VERSION 5.7 ;
BUSBITCHARS "[]" ;
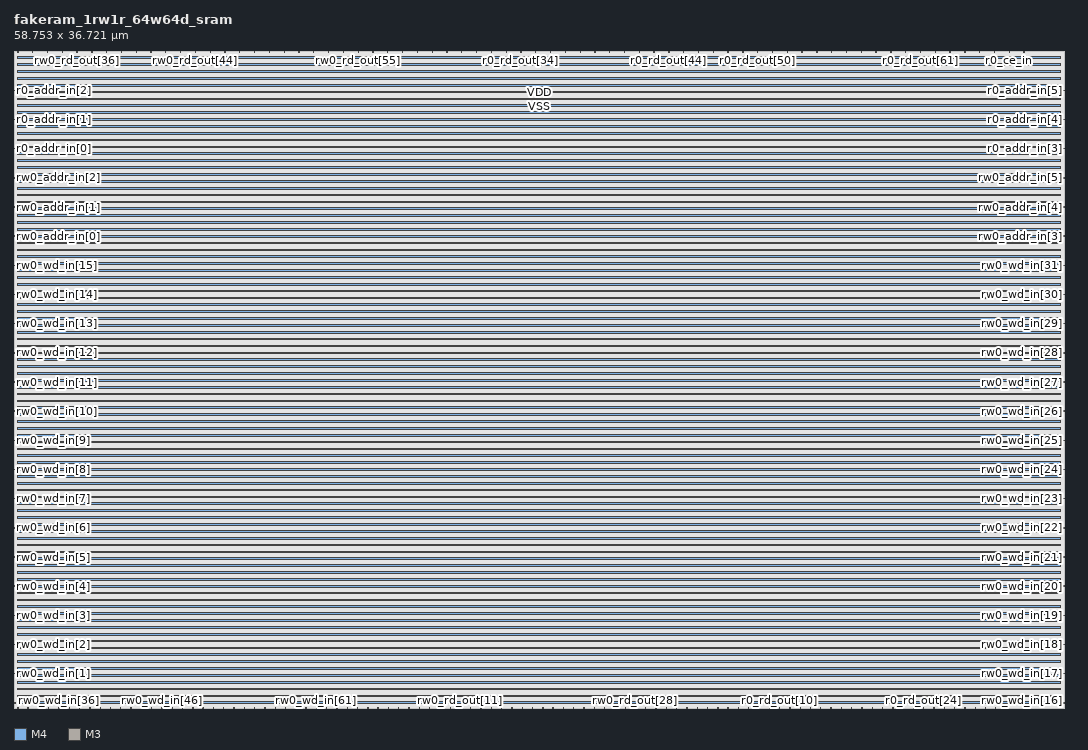
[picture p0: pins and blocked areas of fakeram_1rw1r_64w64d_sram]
MACRO fakeram_1rw1r_64w64d_sram
  FOREIGN fakeram_1rw1r_64w64d_sram 0 0 ;
  SYMMETRY X Y R90 ;
  SIZE 58.753 BY 36.721 ;
  CLASS BLOCK ;
  PIN rw0_wd_in[0]
    DIRECTION INPUT ;
    USE SIGNAL ;
    SHAPE ABUTMENT ;
    PORT
      LAYER M4 ;
      RECT 0.000 0.276 0.072 0.300 ;
    END
  END rw0_wd_in[0]
  PIN rw0_wd_in[1]
    DIRECTION INPUT ;
    USE SIGNAL ;
    SHAPE ABUTMENT ;
    PORT
      LAYER M4 ;
      RECT 0.000 1.908 0.072 1.932 ;
    END
  END rw0_wd_in[1]
  PIN rw0_wd_in[2]
    DIRECTION INPUT ;
    USE SIGNAL ;
    SHAPE ABUTMENT ;
    PORT
      LAYER M4 ;
      RECT 0.000 3.540 0.072 3.564 ;
    END
  END rw0_wd_in[2]
  PIN rw0_wd_in[3]
    DIRECTION INPUT ;
    USE SIGNAL ;
    SHAPE ABUTMENT ;
    PORT
      LAYER M4 ;
      RECT 0.000 5.172 0.072 5.196 ;
    END
  END rw0_wd_in[3]
  PIN rw0_wd_in[4]
    DIRECTION INPUT ;
    USE SIGNAL ;
    SHAPE ABUTMENT ;
    PORT
      LAYER M4 ;
      RECT 0.000 6.804 0.072 6.828 ;
    END
  END rw0_wd_in[4]
  PIN rw0_wd_in[5]
    DIRECTION INPUT ;
    USE SIGNAL ;
    SHAPE ABUTMENT ;
    PORT
      LAYER M4 ;
      RECT 0.000 8.436 0.072 8.460 ;
    END
  END rw0_wd_in[5]
  PIN rw0_wd_in[6]
    DIRECTION INPUT ;
    USE SIGNAL ;
    SHAPE ABUTMENT ;
    PORT
      LAYER M4 ;
      RECT 0.000 10.068 0.072 10.092 ;
    END
  END rw0_wd_in[6]
  PIN rw0_wd_in[7]
    DIRECTION INPUT ;
    USE SIGNAL ;
    SHAPE ABUTMENT ;
    PORT
      LAYER M4 ;
      RECT 0.000 11.700 0.072 11.724 ;
    END
  END rw0_wd_in[7]
  PIN rw0_wd_in[8]
    DIRECTION INPUT ;
    USE SIGNAL ;
    SHAPE ABUTMENT ;
    PORT
      LAYER M4 ;
      RECT 0.000 13.332 0.072 13.356 ;
    END
  END rw0_wd_in[8]
  PIN rw0_wd_in[9]
    DIRECTION INPUT ;
    USE SIGNAL ;
    SHAPE ABUTMENT ;
    PORT
      LAYER M4 ;
      RECT 0.000 14.964 0.072 14.988 ;
    END
  END rw0_wd_in[9]
  PIN rw0_wd_in[10]
    DIRECTION INPUT ;
    USE SIGNAL ;
    SHAPE ABUTMENT ;
    PORT
      LAYER M4 ;
      RECT 0.000 16.596 0.072 16.620 ;
    END
  END rw0_wd_in[10]
  PIN rw0_wd_in[11]
    DIRECTION INPUT ;
    USE SIGNAL ;
    SHAPE ABUTMENT ;
    PORT
      LAYER M4 ;
      RECT 0.000 18.228 0.072 18.252 ;
    END
  END rw0_wd_in[11]
  PIN rw0_wd_in[12]
    DIRECTION INPUT ;
    USE SIGNAL ;
    SHAPE ABUTMENT ;
    PORT
      LAYER M4 ;
      RECT 0.000 19.860 0.072 19.884 ;
    END
  END rw0_wd_in[12]
  PIN rw0_wd_in[13]
    DIRECTION INPUT ;
    USE SIGNAL ;
    SHAPE ABUTMENT ;
    PORT
      LAYER M4 ;
      RECT 0.000 21.492 0.072 21.516 ;
    END
  END rw0_wd_in[13]
  PIN rw0_wd_in[14]
    DIRECTION INPUT ;
    USE SIGNAL ;
    SHAPE ABUTMENT ;
    PORT
      LAYER M4 ;
      RECT 0.000 23.124 0.072 23.148 ;
    END
  END rw0_wd_in[14]
  PIN rw0_wd_in[15]
    DIRECTION INPUT ;
    USE SIGNAL ;
    SHAPE ABUTMENT ;
    PORT
      LAYER M4 ;
      RECT 0.000 24.756 0.072 24.780 ;
    END
  END rw0_wd_in[15]
  PIN rw0_wd_in[16]
    DIRECTION INPUT ;
    USE SIGNAL ;
    SHAPE ABUTMENT ;
    PORT
      LAYER M4 ;
      RECT 58.681 0.276 58.753 0.300 ;
    END
  END rw0_wd_in[16]
  PIN rw0_wd_in[17]
    DIRECTION INPUT ;
    USE SIGNAL ;
    SHAPE ABUTMENT ;
    PORT
      LAYER M4 ;
      RECT 58.681 1.908 58.753 1.932 ;
    END
  END rw0_wd_in[17]
  PIN rw0_wd_in[18]
    DIRECTION INPUT ;
    USE SIGNAL ;
    SHAPE ABUTMENT ;
    PORT
      LAYER M4 ;
      RECT 58.681 3.540 58.753 3.564 ;
    END
  END rw0_wd_in[18]
  PIN rw0_wd_in[19]
    DIRECTION INPUT ;
    USE SIGNAL ;
    SHAPE ABUTMENT ;
    PORT
      LAYER M4 ;
      RECT 58.681 5.172 58.753 5.196 ;
    END
  END rw0_wd_in[19]
  PIN rw0_wd_in[20]
    DIRECTION INPUT ;
    USE SIGNAL ;
    SHAPE ABUTMENT ;
    PORT
      LAYER M4 ;
      RECT 58.681 6.804 58.753 6.828 ;
    END
  END rw0_wd_in[20]
  PIN rw0_wd_in[21]
    DIRECTION INPUT ;
    USE SIGNAL ;
    SHAPE ABUTMENT ;
    PORT
      LAYER M4 ;
      RECT 58.681 8.436 58.753 8.460 ;
    END
  END rw0_wd_in[21]
  PIN rw0_wd_in[22]
    DIRECTION INPUT ;
    USE SIGNAL ;
    SHAPE ABUTMENT ;
    PORT
      LAYER M4 ;
      RECT 58.681 10.068 58.753 10.092 ;
    END
  END rw0_wd_in[22]
  PIN rw0_wd_in[23]
    DIRECTION INPUT ;
    USE SIGNAL ;
    SHAPE ABUTMENT ;
    PORT
      LAYER M4 ;
      RECT 58.681 11.700 58.753 11.724 ;
    END
  END rw0_wd_in[23]
  PIN rw0_wd_in[24]
    DIRECTION INPUT ;
    USE SIGNAL ;
    SHAPE ABUTMENT ;
    PORT
      LAYER M4 ;
      RECT 58.681 13.332 58.753 13.356 ;
    END
  END rw0_wd_in[24]
  PIN rw0_wd_in[25]
    DIRECTION INPUT ;
    USE SIGNAL ;
    SHAPE ABUTMENT ;
    PORT
      LAYER M4 ;
      RECT 58.681 14.964 58.753 14.988 ;
    END
  END rw0_wd_in[25]
  PIN rw0_wd_in[26]
    DIRECTION INPUT ;
    USE SIGNAL ;
    SHAPE ABUTMENT ;
    PORT
      LAYER M4 ;
      RECT 58.681 16.596 58.753 16.620 ;
    END
  END rw0_wd_in[26]
  PIN rw0_wd_in[27]
    DIRECTION INPUT ;
    USE SIGNAL ;
    SHAPE ABUTMENT ;
    PORT
      LAYER M4 ;
      RECT 58.681 18.228 58.753 18.252 ;
    END
  END rw0_wd_in[27]
  PIN rw0_wd_in[28]
    DIRECTION INPUT ;
    USE SIGNAL ;
    SHAPE ABUTMENT ;
    PORT
      LAYER M4 ;
      RECT 58.681 19.860 58.753 19.884 ;
    END
  END rw0_wd_in[28]
  PIN rw0_wd_in[29]
    DIRECTION INPUT ;
    USE SIGNAL ;
    SHAPE ABUTMENT ;
    PORT
      LAYER M4 ;
      RECT 58.681 21.492 58.753 21.516 ;
    END
  END rw0_wd_in[29]
  PIN rw0_wd_in[30]
    DIRECTION INPUT ;
    USE SIGNAL ;
    SHAPE ABUTMENT ;
    PORT
      LAYER M4 ;
      RECT 58.681 23.124 58.753 23.148 ;
    END
  END rw0_wd_in[30]
  PIN rw0_wd_in[31]
    DIRECTION INPUT ;
    USE SIGNAL ;
    SHAPE ABUTMENT ;
    PORT
      LAYER M4 ;
      RECT 58.681 24.756 58.753 24.780 ;
    END
  END rw0_wd_in[31]
  PIN rw0_wd_in[32]
    DIRECTION INPUT ;
    USE SIGNAL ;
    SHAPE ABUTMENT ;
    PORT
      LAYER M3 ;
      RECT 0.207 0.000 0.225 0.054 ;
    END
  END rw0_wd_in[32]
  PIN rw0_wd_in[33]
    DIRECTION INPUT ;
    USE SIGNAL ;
    SHAPE ABUTMENT ;
    PORT
      LAYER M3 ;
      RECT 0.783 0.000 0.801 0.054 ;
    END
  END rw0_wd_in[33]
  PIN rw0_wd_in[34]
    DIRECTION INPUT ;
    USE SIGNAL ;
    SHAPE ABUTMENT ;
    PORT
      LAYER M3 ;
      RECT 1.359 0.000 1.377 0.054 ;
    END
  END rw0_wd_in[34]
  PIN rw0_wd_in[35]
    DIRECTION INPUT ;
    USE SIGNAL ;
    SHAPE ABUTMENT ;
    PORT
      LAYER M3 ;
      RECT 1.935 0.000 1.953 0.054 ;
    END
  END rw0_wd_in[35]
  PIN rw0_wd_in[36]
    DIRECTION INPUT ;
    USE SIGNAL ;
    SHAPE ABUTMENT ;
    PORT
      LAYER M3 ;
      RECT 2.511 0.000 2.529 0.054 ;
    END
  END rw0_wd_in[36]
  PIN rw0_wd_in[37]
    DIRECTION INPUT ;
    USE SIGNAL ;
    SHAPE ABUTMENT ;
    PORT
      LAYER M3 ;
      RECT 3.087 0.000 3.105 0.054 ;
    END
  END rw0_wd_in[37]
  PIN rw0_wd_in[38]
    DIRECTION INPUT ;
    USE SIGNAL ;
    SHAPE ABUTMENT ;
    PORT
      LAYER M3 ;
      RECT 3.663 0.000 3.681 0.054 ;
    END
  END rw0_wd_in[38]
  PIN rw0_wd_in[39]
    DIRECTION INPUT ;
    USE SIGNAL ;
    SHAPE ABUTMENT ;
    PORT
      LAYER M3 ;
      RECT 4.239 0.000 4.257 0.054 ;
    END
  END rw0_wd_in[39]
  PIN rw0_wd_in[40]
    DIRECTION INPUT ;
    USE SIGNAL ;
    SHAPE ABUTMENT ;
    PORT
      LAYER M3 ;
      RECT 4.815 0.000 4.833 0.054 ;
    END
  END rw0_wd_in[40]
  PIN rw0_wd_in[41]
    DIRECTION INPUT ;
    USE SIGNAL ;
    SHAPE ABUTMENT ;
    PORT
      LAYER M3 ;
      RECT 5.391 0.000 5.409 0.054 ;
    END
  END rw0_wd_in[41]
  PIN rw0_wd_in[42]
    DIRECTION INPUT ;
    USE SIGNAL ;
    SHAPE ABUTMENT ;
    PORT
      LAYER M3 ;
      RECT 5.967 0.000 5.985 0.054 ;
    END
  END rw0_wd_in[42]
  PIN rw0_wd_in[43]
    DIRECTION INPUT ;
    USE SIGNAL ;
    SHAPE ABUTMENT ;
    PORT
      LAYER M3 ;
      RECT 6.543 0.000 6.561 0.054 ;
    END
  END rw0_wd_in[43]
  PIN rw0_wd_in[44]
    DIRECTION INPUT ;
    USE SIGNAL ;
    SHAPE ABUTMENT ;
    PORT
      LAYER M3 ;
      RECT 7.119 0.000 7.137 0.054 ;
    END
  END rw0_wd_in[44]
  PIN rw0_wd_in[45]
    DIRECTION INPUT ;
    USE SIGNAL ;
    SHAPE ABUTMENT ;
    PORT
      LAYER M3 ;
      RECT 7.695 0.000 7.713 0.054 ;
    END
  END rw0_wd_in[45]
  PIN rw0_wd_in[46]
    DIRECTION INPUT ;
    USE SIGNAL ;
    SHAPE ABUTMENT ;
    PORT
      LAYER M3 ;
      RECT 8.271 0.000 8.289 0.054 ;
    END
  END rw0_wd_in[46]
  PIN rw0_wd_in[47]
    DIRECTION INPUT ;
    USE SIGNAL ;
    SHAPE ABUTMENT ;
    PORT
      LAYER M3 ;
      RECT 8.847 0.000 8.865 0.054 ;
    END
  END rw0_wd_in[47]
  PIN rw0_wd_in[48]
    DIRECTION INPUT ;
    USE SIGNAL ;
    SHAPE ABUTMENT ;
    PORT
      LAYER M3 ;
      RECT 9.423 0.000 9.441 0.054 ;
    END
  END rw0_wd_in[48]
  PIN rw0_wd_in[49]
    DIRECTION INPUT ;
    USE SIGNAL ;
    SHAPE ABUTMENT ;
    PORT
      LAYER M3 ;
      RECT 9.999 0.000 10.017 0.054 ;
    END
  END rw0_wd_in[49]
  PIN rw0_wd_in[50]
    DIRECTION INPUT ;
    USE SIGNAL ;
    SHAPE ABUTMENT ;
    PORT
      LAYER M3 ;
      RECT 10.575 0.000 10.593 0.054 ;
    END
  END rw0_wd_in[50]
  PIN rw0_wd_in[51]
    DIRECTION INPUT ;
    USE SIGNAL ;
    SHAPE ABUTMENT ;
    PORT
      LAYER M3 ;
      RECT 11.151 0.000 11.169 0.054 ;
    END
  END rw0_wd_in[51]
  PIN rw0_wd_in[52]
    DIRECTION INPUT ;
    USE SIGNAL ;
    SHAPE ABUTMENT ;
    PORT
      LAYER M3 ;
      RECT 11.727 0.000 11.745 0.054 ;
    END
  END rw0_wd_in[52]
  PIN rw0_wd_in[53]
    DIRECTION INPUT ;
    USE SIGNAL ;
    SHAPE ABUTMENT ;
    PORT
      LAYER M3 ;
      RECT 12.303 0.000 12.321 0.054 ;
    END
  END rw0_wd_in[53]
  PIN rw0_wd_in[54]
    DIRECTION INPUT ;
    USE SIGNAL ;
    SHAPE ABUTMENT ;
    PORT
      LAYER M3 ;
      RECT 12.879 0.000 12.897 0.054 ;
    END
  END rw0_wd_in[54]
  PIN rw0_wd_in[55]
    DIRECTION INPUT ;
    USE SIGNAL ;
    SHAPE ABUTMENT ;
    PORT
      LAYER M3 ;
      RECT 13.455 0.000 13.473 0.054 ;
    END
  END rw0_wd_in[55]
  PIN rw0_wd_in[56]
    DIRECTION INPUT ;
    USE SIGNAL ;
    SHAPE ABUTMENT ;
    PORT
      LAYER M3 ;
      RECT 14.031 0.000 14.049 0.054 ;
    END
  END rw0_wd_in[56]
  PIN rw0_wd_in[57]
    DIRECTION INPUT ;
    USE SIGNAL ;
    SHAPE ABUTMENT ;
    PORT
      LAYER M3 ;
      RECT 14.607 0.000 14.625 0.054 ;
    END
  END rw0_wd_in[57]
  PIN rw0_wd_in[58]
    DIRECTION INPUT ;
    USE SIGNAL ;
    SHAPE ABUTMENT ;
    PORT
      LAYER M3 ;
      RECT 15.183 0.000 15.201 0.054 ;
    END
  END rw0_wd_in[58]
  PIN rw0_wd_in[59]
    DIRECTION INPUT ;
    USE SIGNAL ;
    SHAPE ABUTMENT ;
    PORT
      LAYER M3 ;
      RECT 15.759 0.000 15.777 0.054 ;
    END
  END rw0_wd_in[59]
  PIN rw0_wd_in[60]
    DIRECTION INPUT ;
    USE SIGNAL ;
    SHAPE ABUTMENT ;
    PORT
      LAYER M3 ;
      RECT 16.335 0.000 16.353 0.054 ;
    END
  END rw0_wd_in[60]
  PIN rw0_wd_in[61]
    DIRECTION INPUT ;
    USE SIGNAL ;
    SHAPE ABUTMENT ;
    PORT
      LAYER M3 ;
      RECT 16.911 0.000 16.929 0.054 ;
    END
  END rw0_wd_in[61]
  PIN rw0_wd_in[62]
    DIRECTION INPUT ;
    USE SIGNAL ;
    SHAPE ABUTMENT ;
    PORT
      LAYER M3 ;
      RECT 17.487 0.000 17.505 0.054 ;
    END
  END rw0_wd_in[62]
  PIN rw0_wd_in[63]
    DIRECTION INPUT ;
    USE SIGNAL ;
    SHAPE ABUTMENT ;
    PORT
      LAYER M3 ;
      RECT 18.063 0.000 18.081 0.054 ;
    END
  END rw0_wd_in[63]
  PIN rw0_rd_out[0]
    DIRECTION OUTPUT ;
    USE SIGNAL ;
    SHAPE ABUTMENT ;
    PORT
      LAYER M3 ;
      RECT 18.639 0.000 18.657 0.054 ;
    END
  END rw0_rd_out[0]
  PIN rw0_rd_out[1]
    DIRECTION OUTPUT ;
    USE SIGNAL ;
    SHAPE ABUTMENT ;
    PORT
      LAYER M3 ;
      RECT 19.215 0.000 19.233 0.054 ;
    END
  END rw0_rd_out[1]
  PIN rw0_rd_out[2]
    DIRECTION OUTPUT ;
    USE SIGNAL ;
    SHAPE ABUTMENT ;
    PORT
      LAYER M3 ;
      RECT 19.791 0.000 19.809 0.054 ;
    END
  END rw0_rd_out[2]
  PIN rw0_rd_out[3]
    DIRECTION OUTPUT ;
    USE SIGNAL ;
    SHAPE ABUTMENT ;
    PORT
      LAYER M3 ;
      RECT 20.367 0.000 20.385 0.054 ;
    END
  END rw0_rd_out[3]
  PIN rw0_rd_out[4]
    DIRECTION OUTPUT ;
    USE SIGNAL ;
    SHAPE ABUTMENT ;
    PORT
      LAYER M3 ;
      RECT 20.943 0.000 20.961 0.054 ;
    END
  END rw0_rd_out[4]
  PIN rw0_rd_out[5]
    DIRECTION OUTPUT ;
    USE SIGNAL ;
    SHAPE ABUTMENT ;
    PORT
      LAYER M3 ;
      RECT 21.519 0.000 21.537 0.054 ;
    END
  END rw0_rd_out[5]
  PIN rw0_rd_out[6]
    DIRECTION OUTPUT ;
    USE SIGNAL ;
    SHAPE ABUTMENT ;
    PORT
      LAYER M3 ;
      RECT 22.095 0.000 22.113 0.054 ;
    END
  END rw0_rd_out[6]
  PIN rw0_rd_out[7]
    DIRECTION OUTPUT ;
    USE SIGNAL ;
    SHAPE ABUTMENT ;
    PORT
      LAYER M3 ;
      RECT 22.671 0.000 22.689 0.054 ;
    END
  END rw0_rd_out[7]
  PIN rw0_rd_out[8]
    DIRECTION OUTPUT ;
    USE SIGNAL ;
    SHAPE ABUTMENT ;
    PORT
      LAYER M3 ;
      RECT 23.247 0.000 23.265 0.054 ;
    END
  END rw0_rd_out[8]
  PIN rw0_rd_out[9]
    DIRECTION OUTPUT ;
    USE SIGNAL ;
    SHAPE ABUTMENT ;
    PORT
      LAYER M3 ;
      RECT 23.823 0.000 23.841 0.054 ;
    END
  END rw0_rd_out[9]
  PIN rw0_rd_out[10]
    DIRECTION OUTPUT ;
    USE SIGNAL ;
    SHAPE ABUTMENT ;
    PORT
      LAYER M3 ;
      RECT 24.399 0.000 24.417 0.054 ;
    END
  END rw0_rd_out[10]
  PIN rw0_rd_out[11]
    DIRECTION OUTPUT ;
    USE SIGNAL ;
    SHAPE ABUTMENT ;
    PORT
      LAYER M3 ;
      RECT 24.975 0.000 24.993 0.054 ;
    END
  END rw0_rd_out[11]
  PIN rw0_rd_out[12]
    DIRECTION OUTPUT ;
    USE SIGNAL ;
    SHAPE ABUTMENT ;
    PORT
      LAYER M3 ;
      RECT 25.551 0.000 25.569 0.054 ;
    END
  END rw0_rd_out[12]
  PIN rw0_rd_out[13]
    DIRECTION OUTPUT ;
    USE SIGNAL ;
    SHAPE ABUTMENT ;
    PORT
      LAYER M3 ;
      RECT 26.127 0.000 26.145 0.054 ;
    END
  END rw0_rd_out[13]
  PIN rw0_rd_out[14]
    DIRECTION OUTPUT ;
    USE SIGNAL ;
    SHAPE ABUTMENT ;
    PORT
      LAYER M3 ;
      RECT 26.703 0.000 26.721 0.054 ;
    END
  END rw0_rd_out[14]
  PIN rw0_rd_out[15]
    DIRECTION OUTPUT ;
    USE SIGNAL ;
    SHAPE ABUTMENT ;
    PORT
      LAYER M3 ;
      RECT 27.279 0.000 27.297 0.054 ;
    END
  END rw0_rd_out[15]
  PIN rw0_rd_out[16]
    DIRECTION OUTPUT ;
    USE SIGNAL ;
    SHAPE ABUTMENT ;
    PORT
      LAYER M3 ;
      RECT 27.855 0.000 27.873 0.054 ;
    END
  END rw0_rd_out[16]
  PIN rw0_rd_out[17]
    DIRECTION OUTPUT ;
    USE SIGNAL ;
    SHAPE ABUTMENT ;
    PORT
      LAYER M3 ;
      RECT 28.431 0.000 28.449 0.054 ;
    END
  END rw0_rd_out[17]
  PIN rw0_rd_out[18]
    DIRECTION OUTPUT ;
    USE SIGNAL ;
    SHAPE ABUTMENT ;
    PORT
      LAYER M3 ;
      RECT 29.007 0.000 29.025 0.054 ;
    END
  END rw0_rd_out[18]
  PIN rw0_rd_out[19]
    DIRECTION OUTPUT ;
    USE SIGNAL ;
    SHAPE ABUTMENT ;
    PORT
      LAYER M3 ;
      RECT 29.583 0.000 29.601 0.054 ;
    END
  END rw0_rd_out[19]
  PIN rw0_rd_out[20]
    DIRECTION OUTPUT ;
    USE SIGNAL ;
    SHAPE ABUTMENT ;
    PORT
      LAYER M3 ;
      RECT 30.159 0.000 30.177 0.054 ;
    END
  END rw0_rd_out[20]
  PIN rw0_rd_out[21]
    DIRECTION OUTPUT ;
    USE SIGNAL ;
    SHAPE ABUTMENT ;
    PORT
      LAYER M3 ;
      RECT 30.735 0.000 30.753 0.054 ;
    END
  END rw0_rd_out[21]
  PIN rw0_rd_out[22]
    DIRECTION OUTPUT ;
    USE SIGNAL ;
    SHAPE ABUTMENT ;
    PORT
      LAYER M3 ;
      RECT 31.311 0.000 31.329 0.054 ;
    END
  END rw0_rd_out[22]
  PIN rw0_rd_out[23]
    DIRECTION OUTPUT ;
    USE SIGNAL ;
    SHAPE ABUTMENT ;
    PORT
      LAYER M3 ;
      RECT 31.887 0.000 31.905 0.054 ;
    END
  END rw0_rd_out[23]
  PIN rw0_rd_out[24]
    DIRECTION OUTPUT ;
    USE SIGNAL ;
    SHAPE ABUTMENT ;
    PORT
      LAYER M3 ;
      RECT 32.463 0.000 32.481 0.054 ;
    END
  END rw0_rd_out[24]
  PIN rw0_rd_out[25]
    DIRECTION OUTPUT ;
    USE SIGNAL ;
    SHAPE ABUTMENT ;
    PORT
      LAYER M3 ;
      RECT 33.039 0.000 33.057 0.054 ;
    END
  END rw0_rd_out[25]
  PIN rw0_rd_out[26]
    DIRECTION OUTPUT ;
    USE SIGNAL ;
    SHAPE ABUTMENT ;
    PORT
      LAYER M3 ;
      RECT 33.615 0.000 33.633 0.054 ;
    END
  END rw0_rd_out[26]
  PIN rw0_rd_out[27]
    DIRECTION OUTPUT ;
    USE SIGNAL ;
    SHAPE ABUTMENT ;
    PORT
      LAYER M3 ;
      RECT 34.191 0.000 34.209 0.054 ;
    END
  END rw0_rd_out[27]
  PIN rw0_rd_out[28]
    DIRECTION OUTPUT ;
    USE SIGNAL ;
    SHAPE ABUTMENT ;
    PORT
      LAYER M3 ;
      RECT 34.767 0.000 34.785 0.054 ;
    END
  END rw0_rd_out[28]
  PIN rw0_rd_out[29]
    DIRECTION OUTPUT ;
    USE SIGNAL ;
    SHAPE ABUTMENT ;
    PORT
      LAYER M3 ;
      RECT 35.343 0.000 35.361 0.054 ;
    END
  END rw0_rd_out[29]
  PIN rw0_rd_out[30]
    DIRECTION OUTPUT ;
    USE SIGNAL ;
    SHAPE ABUTMENT ;
    PORT
      LAYER M3 ;
      RECT 35.919 0.000 35.937 0.054 ;
    END
  END rw0_rd_out[30]
  PIN rw0_rd_out[31]
    DIRECTION OUTPUT ;
    USE SIGNAL ;
    SHAPE ABUTMENT ;
    PORT
      LAYER M3 ;
      RECT 36.495 0.000 36.513 0.054 ;
    END
  END rw0_rd_out[31]
  PIN rw0_rd_out[32]
    DIRECTION OUTPUT ;
    USE SIGNAL ;
    SHAPE ABUTMENT ;
    PORT
      LAYER M3 ;
      RECT 0.207 36.667 0.225 36.721 ;
    END
  END rw0_rd_out[32]
  PIN rw0_rd_out[33]
    DIRECTION OUTPUT ;
    USE SIGNAL ;
    SHAPE ABUTMENT ;
    PORT
      LAYER M3 ;
      RECT 1.035 36.667 1.053 36.721 ;
    END
  END rw0_rd_out[33]
  PIN rw0_rd_out[34]
    DIRECTION OUTPUT ;
    USE SIGNAL ;
    SHAPE ABUTMENT ;
    PORT
      LAYER M3 ;
      RECT 1.863 36.667 1.881 36.721 ;
    END
  END rw0_rd_out[34]
  PIN rw0_rd_out[35]
    DIRECTION OUTPUT ;
    USE SIGNAL ;
    SHAPE ABUTMENT ;
    PORT
      LAYER M3 ;
      RECT 2.691 36.667 2.709 36.721 ;
    END
  END rw0_rd_out[35]
  PIN rw0_rd_out[36]
    DIRECTION OUTPUT ;
    USE SIGNAL ;
    SHAPE ABUTMENT ;
    PORT
      LAYER M3 ;
      RECT 3.519 36.667 3.537 36.721 ;
    END
  END rw0_rd_out[36]
  PIN rw0_rd_out[37]
    DIRECTION OUTPUT ;
    USE SIGNAL ;
    SHAPE ABUTMENT ;
    PORT
      LAYER M3 ;
      RECT 4.347 36.667 4.365 36.721 ;
    END
  END rw0_rd_out[37]
  PIN rw0_rd_out[38]
    DIRECTION OUTPUT ;
    USE SIGNAL ;
    SHAPE ABUTMENT ;
    PORT
      LAYER M3 ;
      RECT 5.175 36.667 5.193 36.721 ;
    END
  END rw0_rd_out[38]
  PIN rw0_rd_out[39]
    DIRECTION OUTPUT ;
    USE SIGNAL ;
    SHAPE ABUTMENT ;
    PORT
      LAYER M3 ;
      RECT 6.003 36.667 6.021 36.721 ;
    END
  END rw0_rd_out[39]
  PIN rw0_rd_out[40]
    DIRECTION OUTPUT ;
    USE SIGNAL ;
    SHAPE ABUTMENT ;
    PORT
      LAYER M3 ;
      RECT 6.831 36.667 6.849 36.721 ;
    END
  END rw0_rd_out[40]
  PIN rw0_rd_out[41]
    DIRECTION OUTPUT ;
    USE SIGNAL ;
    SHAPE ABUTMENT ;
    PORT
      LAYER M3 ;
      RECT 7.659 36.667 7.677 36.721 ;
    END
  END rw0_rd_out[41]
  PIN rw0_rd_out[42]
    DIRECTION OUTPUT ;
    USE SIGNAL ;
    SHAPE ABUTMENT ;
    PORT
      LAYER M3 ;
      RECT 8.487 36.667 8.505 36.721 ;
    END
  END rw0_rd_out[42]
  PIN rw0_rd_out[43]
    DIRECTION OUTPUT ;
    USE SIGNAL ;
    SHAPE ABUTMENT ;
    PORT
      LAYER M3 ;
      RECT 9.315 36.667 9.333 36.721 ;
    END
  END rw0_rd_out[43]
  PIN rw0_rd_out[44]
    DIRECTION OUTPUT ;
    USE SIGNAL ;
    SHAPE ABUTMENT ;
    PORT
      LAYER M3 ;
      RECT 10.143 36.667 10.161 36.721 ;
    END
  END rw0_rd_out[44]
  PIN rw0_rd_out[45]
    DIRECTION OUTPUT ;
    USE SIGNAL ;
    SHAPE ABUTMENT ;
    PORT
      LAYER M3 ;
      RECT 10.971 36.667 10.989 36.721 ;
    END
  END rw0_rd_out[45]
  PIN rw0_rd_out[46]
    DIRECTION OUTPUT ;
    USE SIGNAL ;
    SHAPE ABUTMENT ;
    PORT
      LAYER M3 ;
      RECT 11.799 36.667 11.817 36.721 ;
    END
  END rw0_rd_out[46]
  PIN rw0_rd_out[47]
    DIRECTION OUTPUT ;
    USE SIGNAL ;
    SHAPE ABUTMENT ;
    PORT
      LAYER M3 ;
      RECT 12.627 36.667 12.645 36.721 ;
    END
  END rw0_rd_out[47]
  PIN rw0_rd_out[48]
    DIRECTION OUTPUT ;
    USE SIGNAL ;
    SHAPE ABUTMENT ;
    PORT
      LAYER M3 ;
      RECT 13.455 36.667 13.473 36.721 ;
    END
  END rw0_rd_out[48]
  PIN rw0_rd_out[49]
    DIRECTION OUTPUT ;
    USE SIGNAL ;
    SHAPE ABUTMENT ;
    PORT
      LAYER M3 ;
      RECT 14.283 36.667 14.301 36.721 ;
    END
  END rw0_rd_out[49]
  PIN rw0_rd_out[50]
    DIRECTION OUTPUT ;
    USE SIGNAL ;
    SHAPE ABUTMENT ;
    PORT
      LAYER M3 ;
      RECT 15.111 36.667 15.129 36.721 ;
    END
  END rw0_rd_out[50]
  PIN rw0_rd_out[51]
    DIRECTION OUTPUT ;
    USE SIGNAL ;
    SHAPE ABUTMENT ;
    PORT
      LAYER M3 ;
      RECT 15.939 36.667 15.957 36.721 ;
    END
  END rw0_rd_out[51]
  PIN rw0_rd_out[52]
    DIRECTION OUTPUT ;
    USE SIGNAL ;
    SHAPE ABUTMENT ;
    PORT
      LAYER M3 ;
      RECT 16.767 36.667 16.785 36.721 ;
    END
  END rw0_rd_out[52]
  PIN rw0_rd_out[53]
    DIRECTION OUTPUT ;
    USE SIGNAL ;
    SHAPE ABUTMENT ;
    PORT
      LAYER M3 ;
      RECT 17.595 36.667 17.613 36.721 ;
    END
  END rw0_rd_out[53]
  PIN rw0_rd_out[54]
    DIRECTION OUTPUT ;
    USE SIGNAL ;
    SHAPE ABUTMENT ;
    PORT
      LAYER M3 ;
      RECT 18.423 36.667 18.441 36.721 ;
    END
  END rw0_rd_out[54]
  PIN rw0_rd_out[55]
    DIRECTION OUTPUT ;
    USE SIGNAL ;
    SHAPE ABUTMENT ;
    PORT
      LAYER M3 ;
      RECT 19.251 36.667 19.269 36.721 ;
    END
  END rw0_rd_out[55]
  PIN rw0_rd_out[56]
    DIRECTION OUTPUT ;
    USE SIGNAL ;
    SHAPE ABUTMENT ;
    PORT
      LAYER M3 ;
      RECT 20.079 36.667 20.097 36.721 ;
    END
  END rw0_rd_out[56]
  PIN rw0_rd_out[57]
    DIRECTION OUTPUT ;
    USE SIGNAL ;
    SHAPE ABUTMENT ;
    PORT
      LAYER M3 ;
      RECT 20.907 36.667 20.925 36.721 ;
    END
  END rw0_rd_out[57]
  PIN rw0_rd_out[58]
    DIRECTION OUTPUT ;
    USE SIGNAL ;
    SHAPE ABUTMENT ;
    PORT
      LAYER M3 ;
      RECT 21.735 36.667 21.753 36.721 ;
    END
  END rw0_rd_out[58]
  PIN rw0_rd_out[59]
    DIRECTION OUTPUT ;
    USE SIGNAL ;
    SHAPE ABUTMENT ;
    PORT
      LAYER M3 ;
      RECT 22.563 36.667 22.581 36.721 ;
    END
  END rw0_rd_out[59]
  PIN rw0_rd_out[60]
    DIRECTION OUTPUT ;
    USE SIGNAL ;
    SHAPE ABUTMENT ;
    PORT
      LAYER M3 ;
      RECT 23.391 36.667 23.409 36.721 ;
    END
  END rw0_rd_out[60]
  PIN rw0_rd_out[61]
    DIRECTION OUTPUT ;
    USE SIGNAL ;
    SHAPE ABUTMENT ;
    PORT
      LAYER M3 ;
      RECT 24.219 36.667 24.237 36.721 ;
    END
  END rw0_rd_out[61]
  PIN rw0_rd_out[62]
    DIRECTION OUTPUT ;
    USE SIGNAL ;
    SHAPE ABUTMENT ;
    PORT
      LAYER M3 ;
      RECT 25.047 36.667 25.065 36.721 ;
    END
  END rw0_rd_out[62]
  PIN rw0_rd_out[63]
    DIRECTION OUTPUT ;
    USE SIGNAL ;
    SHAPE ABUTMENT ;
    PORT
      LAYER M3 ;
      RECT 25.875 36.667 25.893 36.721 ;
    END
  END rw0_rd_out[63]
  PIN r0_rd_out[0]
    DIRECTION OUTPUT ;
    USE SIGNAL ;
    SHAPE ABUTMENT ;
    PORT
      LAYER M3 ;
      RECT 37.071 0.000 37.089 0.054 ;
    END
  END r0_rd_out[0]
  PIN r0_rd_out[1]
    DIRECTION OUTPUT ;
    USE SIGNAL ;
    SHAPE ABUTMENT ;
    PORT
      LAYER M3 ;
      RECT 37.647 0.000 37.665 0.054 ;
    END
  END r0_rd_out[1]
  PIN r0_rd_out[2]
    DIRECTION OUTPUT ;
    USE SIGNAL ;
    SHAPE ABUTMENT ;
    PORT
      LAYER M3 ;
      RECT 38.223 0.000 38.241 0.054 ;
    END
  END r0_rd_out[2]
  PIN r0_rd_out[3]
    DIRECTION OUTPUT ;
    USE SIGNAL ;
    SHAPE ABUTMENT ;
    PORT
      LAYER M3 ;
      RECT 38.799 0.000 38.817 0.054 ;
    END
  END r0_rd_out[3]
  PIN r0_rd_out[4]
    DIRECTION OUTPUT ;
    USE SIGNAL ;
    SHAPE ABUTMENT ;
    PORT
      LAYER M3 ;
      RECT 39.375 0.000 39.393 0.054 ;
    END
  END r0_rd_out[4]
  PIN r0_rd_out[5]
    DIRECTION OUTPUT ;
    USE SIGNAL ;
    SHAPE ABUTMENT ;
    PORT
      LAYER M3 ;
      RECT 39.951 0.000 39.969 0.054 ;
    END
  END r0_rd_out[5]
  PIN r0_rd_out[6]
    DIRECTION OUTPUT ;
    USE SIGNAL ;
    SHAPE ABUTMENT ;
    PORT
      LAYER M3 ;
      RECT 40.527 0.000 40.545 0.054 ;
    END
  END r0_rd_out[6]
  PIN r0_rd_out[7]
    DIRECTION OUTPUT ;
    USE SIGNAL ;
    SHAPE ABUTMENT ;
    PORT
      LAYER M3 ;
      RECT 41.103 0.000 41.121 0.054 ;
    END
  END r0_rd_out[7]
  PIN r0_rd_out[8]
    DIRECTION OUTPUT ;
    USE SIGNAL ;
    SHAPE ABUTMENT ;
    PORT
      LAYER M3 ;
      RECT 41.679 0.000 41.697 0.054 ;
    END
  END r0_rd_out[8]
  PIN r0_rd_out[9]
    DIRECTION OUTPUT ;
    USE SIGNAL ;
    SHAPE ABUTMENT ;
    PORT
      LAYER M3 ;
      RECT 42.255 0.000 42.273 0.054 ;
    END
  END r0_rd_out[9]
  PIN r0_rd_out[10]
    DIRECTION OUTPUT ;
    USE SIGNAL ;
    SHAPE ABUTMENT ;
    PORT
      LAYER M3 ;
      RECT 42.831 0.000 42.849 0.054 ;
    END
  END r0_rd_out[10]
  PIN r0_rd_out[11]
    DIRECTION OUTPUT ;
    USE SIGNAL ;
    SHAPE ABUTMENT ;
    PORT
      LAYER M3 ;
      RECT 43.407 0.000 43.425 0.054 ;
    END
  END r0_rd_out[11]
  PIN r0_rd_out[12]
    DIRECTION OUTPUT ;
    USE SIGNAL ;
    SHAPE ABUTMENT ;
    PORT
      LAYER M3 ;
      RECT 43.983 0.000 44.001 0.054 ;
    END
  END r0_rd_out[12]
  PIN r0_rd_out[13]
    DIRECTION OUTPUT ;
    USE SIGNAL ;
    SHAPE ABUTMENT ;
    PORT
      LAYER M3 ;
      RECT 44.559 0.000 44.577 0.054 ;
    END
  END r0_rd_out[13]
  PIN r0_rd_out[14]
    DIRECTION OUTPUT ;
    USE SIGNAL ;
    SHAPE ABUTMENT ;
    PORT
      LAYER M3 ;
      RECT 45.135 0.000 45.153 0.054 ;
    END
  END r0_rd_out[14]
  PIN r0_rd_out[15]
    DIRECTION OUTPUT ;
    USE SIGNAL ;
    SHAPE ABUTMENT ;
    PORT
      LAYER M3 ;
      RECT 45.711 0.000 45.729 0.054 ;
    END
  END r0_rd_out[15]
  PIN r0_rd_out[16]
    DIRECTION OUTPUT ;
    USE SIGNAL ;
    SHAPE ABUTMENT ;
    PORT
      LAYER M3 ;
      RECT 46.287 0.000 46.305 0.054 ;
    END
  END r0_rd_out[16]
  PIN r0_rd_out[17]
    DIRECTION OUTPUT ;
    USE SIGNAL ;
    SHAPE ABUTMENT ;
    PORT
      LAYER M3 ;
      RECT 46.863 0.000 46.881 0.054 ;
    END
  END r0_rd_out[17]
  PIN r0_rd_out[18]
    DIRECTION OUTPUT ;
    USE SIGNAL ;
    SHAPE ABUTMENT ;
    PORT
      LAYER M3 ;
      RECT 47.439 0.000 47.457 0.054 ;
    END
  END r0_rd_out[18]
  PIN r0_rd_out[19]
    DIRECTION OUTPUT ;
    USE SIGNAL ;
    SHAPE ABUTMENT ;
    PORT
      LAYER M3 ;
      RECT 48.015 0.000 48.033 0.054 ;
    END
  END r0_rd_out[19]
  PIN r0_rd_out[20]
    DIRECTION OUTPUT ;
    USE SIGNAL ;
    SHAPE ABUTMENT ;
    PORT
      LAYER M3 ;
      RECT 48.591 0.000 48.609 0.054 ;
    END
  END r0_rd_out[20]
  PIN r0_rd_out[21]
    DIRECTION OUTPUT ;
    USE SIGNAL ;
    SHAPE ABUTMENT ;
    PORT
      LAYER M3 ;
      RECT 49.167 0.000 49.185 0.054 ;
    END
  END r0_rd_out[21]
  PIN r0_rd_out[22]
    DIRECTION OUTPUT ;
    USE SIGNAL ;
    SHAPE ABUTMENT ;
    PORT
      LAYER M3 ;
      RECT 49.743 0.000 49.761 0.054 ;
    END
  END r0_rd_out[22]
  PIN r0_rd_out[23]
    DIRECTION OUTPUT ;
    USE SIGNAL ;
    SHAPE ABUTMENT ;
    PORT
      LAYER M3 ;
      RECT 50.319 0.000 50.337 0.054 ;
    END
  END r0_rd_out[23]
  PIN r0_rd_out[24]
    DIRECTION OUTPUT ;
    USE SIGNAL ;
    SHAPE ABUTMENT ;
    PORT
      LAYER M3 ;
      RECT 50.895 0.000 50.913 0.054 ;
    END
  END r0_rd_out[24]
  PIN r0_rd_out[25]
    DIRECTION OUTPUT ;
    USE SIGNAL ;
    SHAPE ABUTMENT ;
    PORT
      LAYER M3 ;
      RECT 51.471 0.000 51.489 0.054 ;
    END
  END r0_rd_out[25]
  PIN r0_rd_out[26]
    DIRECTION OUTPUT ;
    USE SIGNAL ;
    SHAPE ABUTMENT ;
    PORT
      LAYER M3 ;
      RECT 52.047 0.000 52.065 0.054 ;
    END
  END r0_rd_out[26]
  PIN r0_rd_out[27]
    DIRECTION OUTPUT ;
    USE SIGNAL ;
    SHAPE ABUTMENT ;
    PORT
      LAYER M3 ;
      RECT 52.623 0.000 52.641 0.054 ;
    END
  END r0_rd_out[27]
  PIN r0_rd_out[28]
    DIRECTION OUTPUT ;
    USE SIGNAL ;
    SHAPE ABUTMENT ;
    PORT
      LAYER M3 ;
      RECT 53.199 0.000 53.217 0.054 ;
    END
  END r0_rd_out[28]
  PIN r0_rd_out[29]
    DIRECTION OUTPUT ;
    USE SIGNAL ;
    SHAPE ABUTMENT ;
    PORT
      LAYER M3 ;
      RECT 53.775 0.000 53.793 0.054 ;
    END
  END r0_rd_out[29]
  PIN r0_rd_out[30]
    DIRECTION OUTPUT ;
    USE SIGNAL ;
    SHAPE ABUTMENT ;
    PORT
      LAYER M3 ;
      RECT 54.351 0.000 54.369 0.054 ;
    END
  END r0_rd_out[30]
  PIN r0_rd_out[31]
    DIRECTION OUTPUT ;
    USE SIGNAL ;
    SHAPE ABUTMENT ;
    PORT
      LAYER M3 ;
      RECT 54.927 0.000 54.945 0.054 ;
    END
  END r0_rd_out[31]
  PIN r0_rd_out[32]
    DIRECTION OUTPUT ;
    USE SIGNAL ;
    SHAPE ABUTMENT ;
    PORT
      LAYER M3 ;
      RECT 26.703 36.667 26.721 36.721 ;
    END
  END r0_rd_out[32]
  PIN r0_rd_out[33]
    DIRECTION OUTPUT ;
    USE SIGNAL ;
    SHAPE ABUTMENT ;
    PORT
      LAYER M3 ;
      RECT 27.531 36.667 27.549 36.721 ;
    END
  END r0_rd_out[33]
  PIN r0_rd_out[34]
    DIRECTION OUTPUT ;
    USE SIGNAL ;
    SHAPE ABUTMENT ;
    PORT
      LAYER M3 ;
      RECT 28.359 36.667 28.377 36.721 ;
    END
  END r0_rd_out[34]
  PIN r0_rd_out[35]
    DIRECTION OUTPUT ;
    USE SIGNAL ;
    SHAPE ABUTMENT ;
    PORT
      LAYER M3 ;
      RECT 29.187 36.667 29.205 36.721 ;
    END
  END r0_rd_out[35]
  PIN r0_rd_out[36]
    DIRECTION OUTPUT ;
    USE SIGNAL ;
    SHAPE ABUTMENT ;
    PORT
      LAYER M3 ;
      RECT 30.015 36.667 30.033 36.721 ;
    END
  END r0_rd_out[36]
  PIN r0_rd_out[37]
    DIRECTION OUTPUT ;
    USE SIGNAL ;
    SHAPE ABUTMENT ;
    PORT
      LAYER M3 ;
      RECT 30.843 36.667 30.861 36.721 ;
    END
  END r0_rd_out[37]
  PIN r0_rd_out[38]
    DIRECTION OUTPUT ;
    USE SIGNAL ;
    SHAPE ABUTMENT ;
    PORT
      LAYER M3 ;
      RECT 31.671 36.667 31.689 36.721 ;
    END
  END r0_rd_out[38]
  PIN r0_rd_out[39]
    DIRECTION OUTPUT ;
    USE SIGNAL ;
    SHAPE ABUTMENT ;
    PORT
      LAYER M3 ;
      RECT 32.499 36.667 32.517 36.721 ;
    END
  END r0_rd_out[39]
  PIN r0_rd_out[40]
    DIRECTION OUTPUT ;
    USE SIGNAL ;
    SHAPE ABUTMENT ;
    PORT
      LAYER M3 ;
      RECT 33.327 36.667 33.345 36.721 ;
    END
  END r0_rd_out[40]
  PIN r0_rd_out[41]
    DIRECTION OUTPUT ;
    USE SIGNAL ;
    SHAPE ABUTMENT ;
    PORT
      LAYER M3 ;
      RECT 34.155 36.667 34.173 36.721 ;
    END
  END r0_rd_out[41]
  PIN r0_rd_out[42]
    DIRECTION OUTPUT ;
    USE SIGNAL ;
    SHAPE ABUTMENT ;
    PORT
      LAYER M3 ;
      RECT 34.983 36.667 35.001 36.721 ;
    END
  END r0_rd_out[42]
  PIN r0_rd_out[43]
    DIRECTION OUTPUT ;
    USE SIGNAL ;
    SHAPE ABUTMENT ;
    PORT
      LAYER M3 ;
      RECT 35.811 36.667 35.829 36.721 ;
    END
  END r0_rd_out[43]
  PIN r0_rd_out[44]
    DIRECTION OUTPUT ;
    USE SIGNAL ;
    SHAPE ABUTMENT ;
    PORT
      LAYER M3 ;
      RECT 36.639 36.667 36.657 36.721 ;
    END
  END r0_rd_out[44]
  PIN r0_rd_out[45]
    DIRECTION OUTPUT ;
    USE SIGNAL ;
    SHAPE ABUTMENT ;
    PORT
      LAYER M3 ;
      RECT 37.467 36.667 37.485 36.721 ;
    END
  END r0_rd_out[45]
  PIN r0_rd_out[46]
    DIRECTION OUTPUT ;
    USE SIGNAL ;
    SHAPE ABUTMENT ;
    PORT
      LAYER M3 ;
      RECT 38.295 36.667 38.313 36.721 ;
    END
  END r0_rd_out[46]
  PIN r0_rd_out[47]
    DIRECTION OUTPUT ;
    USE SIGNAL ;
    SHAPE ABUTMENT ;
    PORT
      LAYER M3 ;
      RECT 39.123 36.667 39.141 36.721 ;
    END
  END r0_rd_out[47]
  PIN r0_rd_out[48]
    DIRECTION OUTPUT ;
    USE SIGNAL ;
    SHAPE ABUTMENT ;
    PORT
      LAYER M3 ;
      RECT 39.951 36.667 39.969 36.721 ;
    END
  END r0_rd_out[48]
  PIN r0_rd_out[49]
    DIRECTION OUTPUT ;
    USE SIGNAL ;
    SHAPE ABUTMENT ;
    PORT
      LAYER M3 ;
      RECT 40.779 36.667 40.797 36.721 ;
    END
  END r0_rd_out[49]
  PIN r0_rd_out[50]
    DIRECTION OUTPUT ;
    USE SIGNAL ;
    SHAPE ABUTMENT ;
    PORT
      LAYER M3 ;
      RECT 41.607 36.667 41.625 36.721 ;
    END
  END r0_rd_out[50]
  PIN r0_rd_out[51]
    DIRECTION OUTPUT ;
    USE SIGNAL ;
    SHAPE ABUTMENT ;
    PORT
      LAYER M3 ;
      RECT 42.435 36.667 42.453 36.721 ;
    END
  END r0_rd_out[51]
  PIN r0_rd_out[52]
    DIRECTION OUTPUT ;
    USE SIGNAL ;
    SHAPE ABUTMENT ;
    PORT
      LAYER M3 ;
      RECT 43.263 36.667 43.281 36.721 ;
    END
  END r0_rd_out[52]
  PIN r0_rd_out[53]
    DIRECTION OUTPUT ;
    USE SIGNAL ;
    SHAPE ABUTMENT ;
    PORT
      LAYER M3 ;
      RECT 44.091 36.667 44.109 36.721 ;
    END
  END r0_rd_out[53]
  PIN r0_rd_out[54]
    DIRECTION OUTPUT ;
    USE SIGNAL ;
    SHAPE ABUTMENT ;
    PORT
      LAYER M3 ;
      RECT 44.919 36.667 44.937 36.721 ;
    END
  END r0_rd_out[54]
  PIN r0_rd_out[55]
    DIRECTION OUTPUT ;
    USE SIGNAL ;
    SHAPE ABUTMENT ;
    PORT
      LAYER M3 ;
      RECT 45.747 36.667 45.765 36.721 ;
    END
  END r0_rd_out[55]
  PIN r0_rd_out[56]
    DIRECTION OUTPUT ;
    USE SIGNAL ;
    SHAPE ABUTMENT ;
    PORT
      LAYER M3 ;
      RECT 46.575 36.667 46.593 36.721 ;
    END
  END r0_rd_out[56]
  PIN r0_rd_out[57]
    DIRECTION OUTPUT ;
    USE SIGNAL ;
    SHAPE ABUTMENT ;
    PORT
      LAYER M3 ;
      RECT 47.403 36.667 47.421 36.721 ;
    END
  END r0_rd_out[57]
  PIN r0_rd_out[58]
    DIRECTION OUTPUT ;
    USE SIGNAL ;
    SHAPE ABUTMENT ;
    PORT
      LAYER M3 ;
      RECT 48.231 36.667 48.249 36.721 ;
    END
  END r0_rd_out[58]
  PIN r0_rd_out[59]
    DIRECTION OUTPUT ;
    USE SIGNAL ;
    SHAPE ABUTMENT ;
    PORT
      LAYER M3 ;
      RECT 49.059 36.667 49.077 36.721 ;
    END
  END r0_rd_out[59]
  PIN r0_rd_out[60]
    DIRECTION OUTPUT ;
    USE SIGNAL ;
    SHAPE ABUTMENT ;
    PORT
      LAYER M3 ;
      RECT 49.887 36.667 49.905 36.721 ;
    END
  END r0_rd_out[60]
  PIN r0_rd_out[61]
    DIRECTION OUTPUT ;
    USE SIGNAL ;
    SHAPE ABUTMENT ;
    PORT
      LAYER M3 ;
      RECT 50.715 36.667 50.733 36.721 ;
    END
  END r0_rd_out[61]
  PIN r0_rd_out[62]
    DIRECTION OUTPUT ;
    USE SIGNAL ;
    SHAPE ABUTMENT ;
    PORT
      LAYER M3 ;
      RECT 51.543 36.667 51.561 36.721 ;
    END
  END r0_rd_out[62]
  PIN r0_rd_out[63]
    DIRECTION OUTPUT ;
    USE SIGNAL ;
    SHAPE ABUTMENT ;
    PORT
      LAYER M3 ;
      RECT 52.371 36.667 52.389 36.721 ;
    END
  END r0_rd_out[63]
  PIN rw0_addr_in[0]
    DIRECTION INPUT ;
    USE SIGNAL ;
    SHAPE ABUTMENT ;
    PORT
      LAYER M4 ;
      RECT 0.000 26.388 0.072 26.412 ;
    END
  END rw0_addr_in[0]
  PIN rw0_addr_in[1]
    DIRECTION INPUT ;
    USE SIGNAL ;
    SHAPE ABUTMENT ;
    PORT
      LAYER M4 ;
      RECT 0.000 28.020 0.072 28.044 ;
    END
  END rw0_addr_in[1]
  PIN rw0_addr_in[2]
    DIRECTION INPUT ;
    USE SIGNAL ;
    SHAPE ABUTMENT ;
    PORT
      LAYER M4 ;
      RECT 0.000 29.652 0.072 29.676 ;
    END
  END rw0_addr_in[2]
  PIN rw0_addr_in[3]
    DIRECTION INPUT ;
    USE SIGNAL ;
    SHAPE ABUTMENT ;
    PORT
      LAYER M4 ;
      RECT 58.681 26.388 58.753 26.412 ;
    END
  END rw0_addr_in[3]
  PIN rw0_addr_in[4]
    DIRECTION INPUT ;
    USE SIGNAL ;
    SHAPE ABUTMENT ;
    PORT
      LAYER M4 ;
      RECT 58.681 28.020 58.753 28.044 ;
    END
  END rw0_addr_in[4]
  PIN rw0_addr_in[5]
    DIRECTION INPUT ;
    USE SIGNAL ;
    SHAPE ABUTMENT ;
    PORT
      LAYER M4 ;
      RECT 58.681 29.652 58.753 29.676 ;
    END
  END rw0_addr_in[5]
  PIN r0_addr_in[0]
    DIRECTION INPUT ;
    USE SIGNAL ;
    SHAPE ABUTMENT ;
    PORT
      LAYER M4 ;
      RECT 0.000 31.284 0.072 31.308 ;
    END
  END r0_addr_in[0]
  PIN r0_addr_in[1]
    DIRECTION INPUT ;
    USE SIGNAL ;
    SHAPE ABUTMENT ;
    PORT
      LAYER M4 ;
      RECT 0.000 32.916 0.072 32.940 ;
    END
  END r0_addr_in[1]
  PIN r0_addr_in[2]
    DIRECTION INPUT ;
    USE SIGNAL ;
    SHAPE ABUTMENT ;
    PORT
      LAYER M4 ;
      RECT 0.000 34.548 0.072 34.572 ;
    END
  END r0_addr_in[2]
  PIN r0_addr_in[3]
    DIRECTION INPUT ;
    USE SIGNAL ;
    SHAPE ABUTMENT ;
    PORT
      LAYER M4 ;
      RECT 58.681 31.284 58.753 31.308 ;
    END
  END r0_addr_in[3]
  PIN r0_addr_in[4]
    DIRECTION INPUT ;
    USE SIGNAL ;
    SHAPE ABUTMENT ;
    PORT
      LAYER M4 ;
      RECT 58.681 32.916 58.753 32.940 ;
    END
  END r0_addr_in[4]
  PIN r0_addr_in[5]
    DIRECTION INPUT ;
    USE SIGNAL ;
    SHAPE ABUTMENT ;
    PORT
      LAYER M4 ;
      RECT 58.681 34.548 58.753 34.572 ;
    END
  END r0_addr_in[5]
  PIN rw0_we_in
    DIRECTION INPUT ;
    USE SIGNAL ;
    SHAPE ABUTMENT ;
    PORT
      LAYER M3 ;
      RECT 53.199 36.667 53.217 36.721 ;
    END
  END rw0_we_in
  PIN rw0_ce_in
    DIRECTION INPUT ;
    USE SIGNAL ;
    SHAPE ABUTMENT ;
    PORT
      LAYER M3 ;
      RECT 54.027 36.667 54.045 36.721 ;
    END
  END rw0_ce_in
  PIN rw0_clk
    DIRECTION INPUT ;
    USE SIGNAL ;
    SHAPE ABUTMENT ;
    PORT
      LAYER M3 ;
      RECT 54.855 36.667 54.873 36.721 ;
    END
  END rw0_clk
  PIN r0_ce_in
    DIRECTION INPUT ;
    USE SIGNAL ;
    SHAPE ABUTMENT ;
    PORT
      LAYER M3 ;
      RECT 55.683 36.667 55.701 36.721 ;
    END
  END r0_ce_in
  PIN r0_clk
    DIRECTION INPUT ;
    USE SIGNAL ;
    SHAPE ABUTMENT ;
    PORT
      LAYER M3 ;
      RECT 56.511 36.667 56.529 36.721 ;
    END
  END r0_clk
  PIN VSS
    DIRECTION INOUT ;
    USE GROUND ;
    PORT
      LAYER M4 ;
      RECT 0.216 0.240 58.537 0.336 ;
      RECT 0.216 1.008 58.537 1.104 ;
      RECT 0.216 1.776 58.537 1.872 ;
      RECT 0.216 2.544 58.537 2.640 ;
      RECT 0.216 3.312 58.537 3.408 ;
      RECT 0.216 4.080 58.537 4.176 ;
      RECT 0.216 4.848 58.537 4.944 ;
      RECT 0.216 5.616 58.537 5.712 ;
      RECT 0.216 6.384 58.537 6.480 ;
      RECT 0.216 7.152 58.537 7.248 ;
      RECT 0.216 7.920 58.537 8.016 ;
      RECT 0.216 8.688 58.537 8.784 ;
      RECT 0.216 9.456 58.537 9.552 ;
      RECT 0.216 10.224 58.537 10.320 ;
      RECT 0.216 10.992 58.537 11.088 ;
      RECT 0.216 11.760 58.537 11.856 ;
      RECT 0.216 12.528 58.537 12.624 ;
      RECT 0.216 13.296 58.537 13.392 ;
      RECT 0.216 14.064 58.537 14.160 ;
      RECT 0.216 14.832 58.537 14.928 ;
      RECT 0.216 15.600 58.537 15.696 ;
      RECT 0.216 16.368 58.537 16.464 ;
      RECT 0.216 17.136 58.537 17.232 ;
      RECT 0.216 17.904 58.537 18.000 ;
      RECT 0.216 18.672 58.537 18.768 ;
      RECT 0.216 19.440 58.537 19.536 ;
      RECT 0.216 20.208 58.537 20.304 ;
      RECT 0.216 20.976 58.537 21.072 ;
      RECT 0.216 21.744 58.537 21.840 ;
      RECT 0.216 22.512 58.537 22.608 ;
      RECT 0.216 23.280 58.537 23.376 ;
      RECT 0.216 24.048 58.537 24.144 ;
      RECT 0.216 24.816 58.537 24.912 ;
      RECT 0.216 25.584 58.537 25.680 ;
      RECT 0.216 26.352 58.537 26.448 ;
      RECT 0.216 27.120 58.537 27.216 ;
      RECT 0.216 27.888 58.537 27.984 ;
      RECT 0.216 28.656 58.537 28.752 ;
      RECT 0.216 29.424 58.537 29.520 ;
      RECT 0.216 30.192 58.537 30.288 ;
      RECT 0.216 30.960 58.537 31.056 ;
      RECT 0.216 31.728 58.537 31.824 ;
      RECT 0.216 32.496 58.537 32.592 ;
      RECT 0.216 33.264 58.537 33.360 ;
      RECT 0.216 34.032 58.537 34.128 ;
      RECT 0.216 34.800 58.537 34.896 ;
      RECT 0.216 35.568 58.537 35.664 ;
      RECT 0.216 36.336 58.537 36.432 ;
    END
  END VSS
  PIN VDD
    DIRECTION INOUT ;
    USE POWER ;
    PORT
      LAYER M4 ;
      RECT 0.216 0.624 58.537 0.720 ;
      RECT 0.216 1.392 58.537 1.488 ;
      RECT 0.216 2.160 58.537 2.256 ;
      RECT 0.216 2.928 58.537 3.024 ;
      RECT 0.216 3.696 58.537 3.792 ;
      RECT 0.216 4.464 58.537 4.560 ;
      RECT 0.216 5.232 58.537 5.328 ;
      RECT 0.216 6.000 58.537 6.096 ;
      RECT 0.216 6.768 58.537 6.864 ;
      RECT 0.216 7.536 58.537 7.632 ;
      RECT 0.216 8.304 58.537 8.400 ;
      RECT 0.216 9.072 58.537 9.168 ;
      RECT 0.216 9.840 58.537 9.936 ;
      RECT 0.216 10.608 58.537 10.704 ;
      RECT 0.216 11.376 58.537 11.472 ;
      RECT 0.216 12.144 58.537 12.240 ;
      RECT 0.216 12.912 58.537 13.008 ;
      RECT 0.216 13.680 58.537 13.776 ;
      RECT 0.216 14.448 58.537 14.544 ;
      RECT 0.216 15.216 58.537 15.312 ;
      RECT 0.216 15.984 58.537 16.080 ;
      RECT 0.216 16.752 58.537 16.848 ;
      RECT 0.216 17.520 58.537 17.616 ;
      RECT 0.216 18.288 58.537 18.384 ;
      RECT 0.216 19.056 58.537 19.152 ;
      RECT 0.216 19.824 58.537 19.920 ;
      RECT 0.216 20.592 58.537 20.688 ;
      RECT 0.216 21.360 58.537 21.456 ;
      RECT 0.216 22.128 58.537 22.224 ;
      RECT 0.216 22.896 58.537 22.992 ;
      RECT 0.216 23.664 58.537 23.760 ;
      RECT 0.216 24.432 58.537 24.528 ;
      RECT 0.216 25.200 58.537 25.296 ;
      RECT 0.216 25.968 58.537 26.064 ;
      RECT 0.216 26.736 58.537 26.832 ;
      RECT 0.216 27.504 58.537 27.600 ;
      RECT 0.216 28.272 58.537 28.368 ;
      RECT 0.216 29.040 58.537 29.136 ;
      RECT 0.216 29.808 58.537 29.904 ;
      RECT 0.216 30.576 58.537 30.672 ;
      RECT 0.216 31.344 58.537 31.440 ;
      RECT 0.216 32.112 58.537 32.208 ;
      RECT 0.216 32.880 58.537 32.976 ;
      RECT 0.216 33.648 58.537 33.744 ;
      RECT 0.216 34.416 58.537 34.512 ;
      RECT 0.216 35.184 58.537 35.280 ;
      RECT 0.216 35.952 58.537 36.048 ;
    END
  END VDD
  OBS
    LAYER M1 ;
    RECT 0 0 58.753 36.721 ;
    LAYER M2 ;
    RECT 0 0 58.753 36.721 ;
    LAYER M3 ;
    RECT 0 0 58.753 36.721 ;
    LAYER M4 ;
    RECT 0 0 58.753 36.721 ;
  END
END fakeram_1rw1r_64w64d_sram

END LIBRARY
